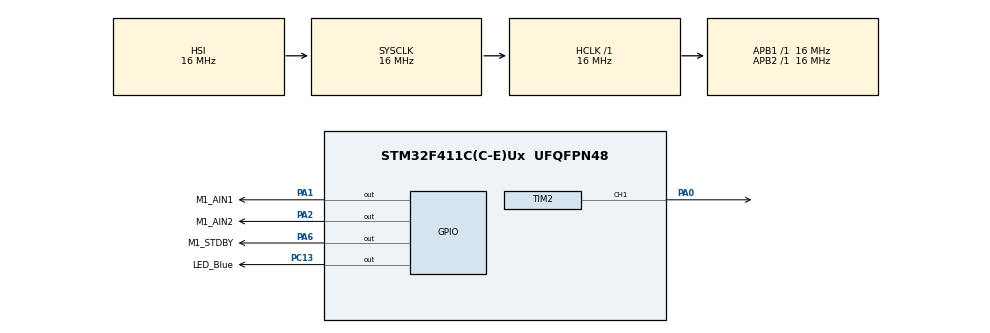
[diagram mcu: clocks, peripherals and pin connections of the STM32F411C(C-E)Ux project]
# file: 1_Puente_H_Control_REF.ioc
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Mcu.Family=STM32F4
Mcu.Name=STM32F411C(C-E)Ux
Mcu.Package=UFQFPN48
NVIC.PriorityGroup=NVIC_PRIORITYGROUP_4
PA0-WKUP.Signal=S_TIM2_CH1_ETR
PA1.GPIO_Label=M1_AIN1
PA1.Signal=GPIO_Output
PA2.GPIO_Label=M1_AIN2
PA2.Signal=GPIO_Output
PA6.GPIO_Label=M1_STDBY
PA6.Signal=GPIO_Output
PC13-ANTI_TAMP.GPIO_Label=LED_Blue
PC13-ANTI_TAMP.Signal=GPIO_Output
ProjectManager.HeapSize=0x200
ProjectManager.StackSize=0x400
ProjectManager.TargetToolchain=STM32CubeIDE
RCC.AHBFreq_Value=16000000
RCC.APB1Freq_Value=16000000
RCC.APB2Freq_Value=16000000
RCC.CortexFreq_Value=16000000
RCC.HSE_VALUE=25000000
RCC.HSI_VALUE=16000000
RCC.LSE_VALUE=32768
RCC.SYSCLKFreq_VALUE=16000000
RCC.VCOOutputFreq_Value=192000000
SH.S_TIM2_CH1_ETR.0=TIM2_CH1,PWM Generation1 CH1
TIM2.AutoReloadPreload=TIM_AUTORELOAD_PRELOAD_ENABLE
TIM2.Channel-PWM\ Generation1\ CH1=TIM_CHANNEL_1
TIM2.Period=499
TIM2.Prescaler=9
board=custom

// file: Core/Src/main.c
/* USER CODE BEGIN Header */
/**
  ******************************************************************************
  * @file           : main.c
  * @brief          : Main program body
  ******************************************************************************
  * @attention
  *
  * Copyright (c) 2026 STMicroelectronics.
  * All rights reserved.
  *
  * This software is licensed under terms that can be found in the LICENSE file
  * in the root directory of this software component.
  * If no LICENSE file comes with this software, it is provided AS-IS.
  *
  ******************************************************************************
  */
/* USER CODE END Header */
#include "main.h"

TIM_HandleTypeDef htim2;

/* USER CODE BEGIN PV */
#define PWM_MAX 499  // ARR value
#define PWM_FULL 499
#define PWM_HALF 250
/* USER CODE END PV */

void SystemClock_Config(void);
static void MX_GPIO_Init(void);
static void MX_TIM2_Init(void);

int main(void)
{

  /* MCU Configuration--------------------------------------------------------*/

  /* Reset of all peripherals, Initializes the Flash interface and the Systick. */
  HAL_Init();

  /* Configure the system clock */
  SystemClock_Config();

  /* Initialize all configured peripherals */
  MX_GPIO_Init();
  MX_TIM2_Init();

  /* USER CODE BEGIN Init2 */
  // se inicializan ambos canales PWM del Timer 2
  HAL_TIM_PWM_Start(&htim2, TIM_CHANNEL_1);  // PA0 - Motor M1
  HAL_TIM_PWM_Start(&htim2, TIM_CHANNEL_2);  // PA3 - Motor M2

  // se habilita el driver (Standby enable PA6)
  HAL_GPIO_WritePin(GPIOA, GPIO_PIN_6, GPIO_PIN_SET);
  /* USER CODE END Init2 */
  /* USER CODE BEGIN 2 */
  // Led para indicar qu efunciona
  HAL_GPIO_TogglePin(LED_Blue_GPIO_Port, LED_Blue_Pin);
  HAL_Delay(200);

  HAL_GPIO_WritePin(GPIOA, GPIO_PIN_1, GPIO_PIN_SET);   // PA1 = HIGH (test GPIO)
  HAL_Delay(500);

  /* USER CODE END 2 */

  /* Infinite loop */
  /* USER CODE BEGIN WHILE */
  while (1)
  {
    // AIN1 = HIGH
    HAL_GPIO_WritePin(GPIOA, GPIO_PIN_1, GPIO_PIN_SET);   // Direction control

    // Setaround 100%
    __HAL_TIM_SET_COMPARE(&htim2, TIM_CHANNEL_1, 400); //
    __HAL_TIM_SET_COMPARE(&htim2, TIM_CHANNEL_2, 400);

    HAL_GPIO_TogglePin(LED_Blue_GPIO_Port, LED_Blue_Pin);
    HAL_Delay(2000);

    /* TEST 2: Motor reverse */
    HAL_GPIO_WritePin(GPIOA, GPIO_PIN_1, GPIO_PIN_RESET);  // Direction control

    __HAL_TIM_SET_COMPARE(&htim2, TIM_CHANNEL_1, 400);
    __HAL_TIM_SET_COMPARE(&htim2, TIM_CHANNEL_2, 400);

    HAL_GPIO_TogglePin(LED_Blue_GPIO_Port, LED_Blue_Pin);
    HAL_Delay(2000);
  }
  /* USER CODE END WHILE */

}

void SystemClock_Config(void)
{
  RCC_OscInitTypeDef RCC_OscInitStruct = {0};
  RCC_ClkInitTypeDef RCC_ClkInitStruct = {0};

  /** Configure the main internal regulator output voltage
  */
  __HAL_RCC_PWR_CLK_ENABLE();
  __HAL_PWR_VOLTAGESCALING_CONFIG(PWR_REGULATOR_VOLTAGE_SCALE1);

  /** Initializes the RCC Oscillators according to the specified parameters
  * in the RCC_OscInitTypeDef structure.
  */
  RCC_OscInitStruct.OscillatorType = RCC_OSCILLATORTYPE_HSI;
  RCC_OscInitStruct.HSIState = RCC_HSI_ON;
  RCC_OscInitStruct.HSICalibrationValue = RCC_HSICALIBRATION_DEFAULT;
  RCC_OscInitStruct.PLL.PLLState = RCC_PLL_NONE;
  if (HAL_RCC_OscConfig(&RCC_OscInitStruct) != HAL_OK)
  {
    Error_Handler();
  }

  /** Initializes the CPU, AHB and APB buses clocks
  */
  RCC_ClkInitStruct.ClockType = RCC_CLOCKTYPE_HCLK|RCC_CLOCKTYPE_SYSCLK
                              |RCC_CLOCKTYPE_PCLK1|RCC_CLOCKTYPE_PCLK2;
  RCC_ClkInitStruct.SYSCLKSource = RCC_SYSCLKSOURCE_HSI;
  RCC_ClkInitStruct.AHBCLKDivider = RCC_SYSCLK_DIV1;
  RCC_ClkInitStruct.APB1CLKDivider = RCC_HCLK_DIV1;
  RCC_ClkInitStruct.APB2CLKDivider = RCC_HCLK_DIV1;

  if (HAL_RCC_ClockConfig(&RCC_ClkInitStruct, FLASH_LATENCY_0) != HAL_OK)
  {
    Error_Handler();
  }
}

static void MX_TIM2_Init(void)
{

  TIM_MasterConfigTypeDef sMasterConfig = {0};
  TIM_OC_InitTypeDef sConfigOC = {0};

  htim2.Instance = TIM2;
  htim2.Init.Prescaler = 9;
  htim2.Init.CounterMode = TIM_COUNTERMODE_UP;
  htim2.Init.Period = 499;
  htim2.Init.ClockDivision = TIM_CLOCKDIVISION_DIV1;
  htim2.Init.AutoReloadPreload = TIM_AUTORELOAD_PRELOAD_ENABLE;
  if (HAL_TIM_PWM_Init(&htim2) != HAL_OK)
  {
    Error_Handler();
  }
  sMasterConfig.MasterOutputTrigger = TIM_TRGO_RESET;
  sMasterConfig.MasterSlaveMode = TIM_MASTERSLAVEMODE_DISABLE;
  if (HAL_TIMEx_MasterConfigSynchronization(&htim2, &sMasterConfig) != HAL_OK)
  {
    Error_Handler();
  }

  /* Configure Channel 1 (PA0 - Motor M1) */
  sConfigOC.OCMode = TIM_OCMODE_PWM1;
  sConfigOC.Pulse = 0;
  sConfigOC.OCPolarity = TIM_OCPOLARITY_HIGH;
  sConfigOC.OCFastMode = TIM_OCFAST_DISABLE;
  if (HAL_TIM_PWM_ConfigChannel(&htim2, &sConfigOC, TIM_CHANNEL_1) != HAL_OK)
  {
    Error_Handler();
  }

  /* Configure Channel 2 (PA3 - Motor M2) */
  sConfigOC.OCMode = TIM_OCMODE_PWM1;
  sConfigOC.Pulse = 0;
  sConfigOC.OCPolarity = TIM_OCPOLARITY_HIGH;
  sConfigOC.OCFastMode = TIM_OCFAST_DISABLE;
  if (HAL_TIM_PWM_ConfigChannel(&htim2, &sConfigOC, TIM_CHANNEL_2) != HAL_OK)
  {
    Error_Handler();
  }

  HAL_TIM_MspPostInit(&htim2);

}

static void MX_GPIO_Init(void)
{
  GPIO_InitTypeDef GPIO_InitStruct = {0};

  /* GPIO Ports Clock Enable */
  __HAL_RCC_GPIOC_CLK_ENABLE();
  __HAL_RCC_GPIOA_CLK_ENABLE();

  /*Configure GPIO pin Output Level */
  HAL_GPIO_WritePin(LED_Blue_GPIO_Port, LED_Blue_Pin, GPIO_PIN_RESET);

  /*Configure GPIO pin Output Level - Control signals initialized to RESET */
  HAL_GPIO_WritePin(GPIOA, GPIO_PIN_1|GPIO_PIN_2|GPIO_PIN_4|GPIO_PIN_5|GPIO_PIN_6, GPIO_PIN_RESET);

  /*Configure GPIO pin : LED_Blue_Pin */
  GPIO_InitStruct.Pin = LED_Blue_Pin;
  GPIO_InitStruct.Mode = GPIO_MODE_OUTPUT_PP;
  GPIO_InitStruct.Pull = GPIO_NOPULL;
  GPIO_InitStruct.Speed = GPIO_SPEED_FREQ_LOW;
  HAL_GPIO_Init(LED_Blue_GPIO_Port, &GPIO_InitStruct);

  /*Configure GPIO pins for Motor Control: AIN1(PA1), AIN2(PA2), BIN1(PA4), BIN2(PA5), STBY(PA6) */
  GPIO_InitStruct.Pin = GPIO_PIN_1|GPIO_PIN_2|GPIO_PIN_4|GPIO_PIN_5|GPIO_PIN_6;
  GPIO_InitStruct.Mode = GPIO_MODE_OUTPUT_PP;
  GPIO_InitStruct.Pull = GPIO_NOPULL;
  GPIO_InitStruct.Speed = GPIO_SPEED_FREQ_LOW;
  HAL_GPIO_Init(GPIOA, &GPIO_InitStruct);

}

void Error_Handler(void)
{
  __disable_irq();
  while (1)
  {
  }
}
